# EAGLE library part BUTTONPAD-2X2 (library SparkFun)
5mm Button Pad Proven layout and schematic for 2x2 button pad. Panelize this device/fp to a 4x4 pad if needed. Spark Fun Electronics SKU : COM-07835. Compatible common cathode tri-color LED SKU : COM-00105

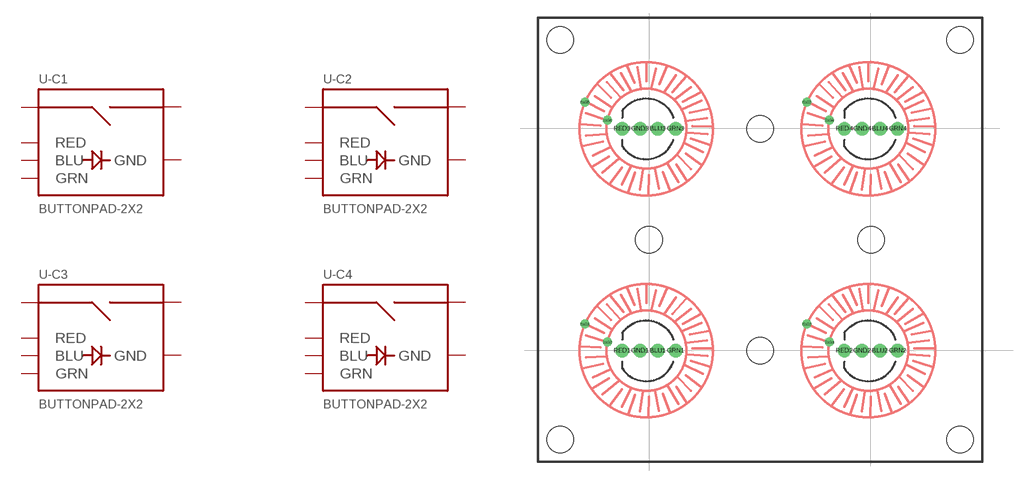
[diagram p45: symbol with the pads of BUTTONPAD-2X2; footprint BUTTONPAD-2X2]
Designator prefix -; gates -C1=BUTTONPAD_SINGLE -C2=BUTTONPAD_SINGLE -C3=BUTTONPAD_SINGLE -C4=BUTTONPAD_SINGLE

## BUTTONPAD-2X2  [BUTTONPAD-2X2]
BLU1  -C1:BLU
BLU2  -C2:BLU
BLU3  -C3:BLU
BLU4  -C4:BLU
GND1  -C1:GND
GND2  -C2:GND
GND3  -C3:GND
GND4  -C4:GND
GRN1  -C1:GRN
GRN2  -C2:GRN
GRN3  -C3:GRN
GRN4  -C4:GRN
RED1  -C1:RED
RED2  -C2:RED
RED3  -C3:RED
RED4  -C4:RED
SIG1  -C1:SIG1
SIG2  -C1:SIG2
SIG3  -C2:SIG1
SIG4  -C2:SIG2
SIG5  -C3:SIG1
SIG6  -C3:SIG2
SIG7  -C4:SIG1
SIG8  -C4:SIG2

## Footprint BUTTONPAD-2X2 (pad centres in mm)
drill 1 round: BLU1 13.5,12.5; BLU2 38.5,12.5; BLU3 13.5,37.5; BLU4 38.5,37.5; GND1 11.5,12.5; GND2 36.5,12.5; GND3 11.5,37.5; GND4 36.5,37.5; GRN1 15.5,12.5; GRN2 40.5,12.5; GRN3 15.5,37.5; GRN4 40.5,37.5; RED1 9.5,12.5; RED2 34.5,12.5; RED3 9.5,37.5; RED4 34.5,37.5
drill 0.508 round: SIG1 5.288,15.513; SIG2 7.828,13.481; SIG3 30.288,15.513; SIG4 32.828,13.481; SIG5 5.288,40.513; SIG6 7.828,38.481; SIG7 30.288,40.513; SIG8 32.828,38.481
hole 3 at 12.5,25
hole 3 at 25,37.5
hole 3 at 37.5,25
hole 3 at 25,12.5
hole 3 at 2.5,2.5
hole 3 at 2.5,47.5
hole 3 at 47.5,47.5
hole 3 at 47.5,2.5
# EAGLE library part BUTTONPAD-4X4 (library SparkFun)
5mm Button Pad Proto layout and schematic for 4x4 button pad. Spark Fun Electronics SKU : COM-07835. Compatible common cathode tri-color LED SKU : COM-00105

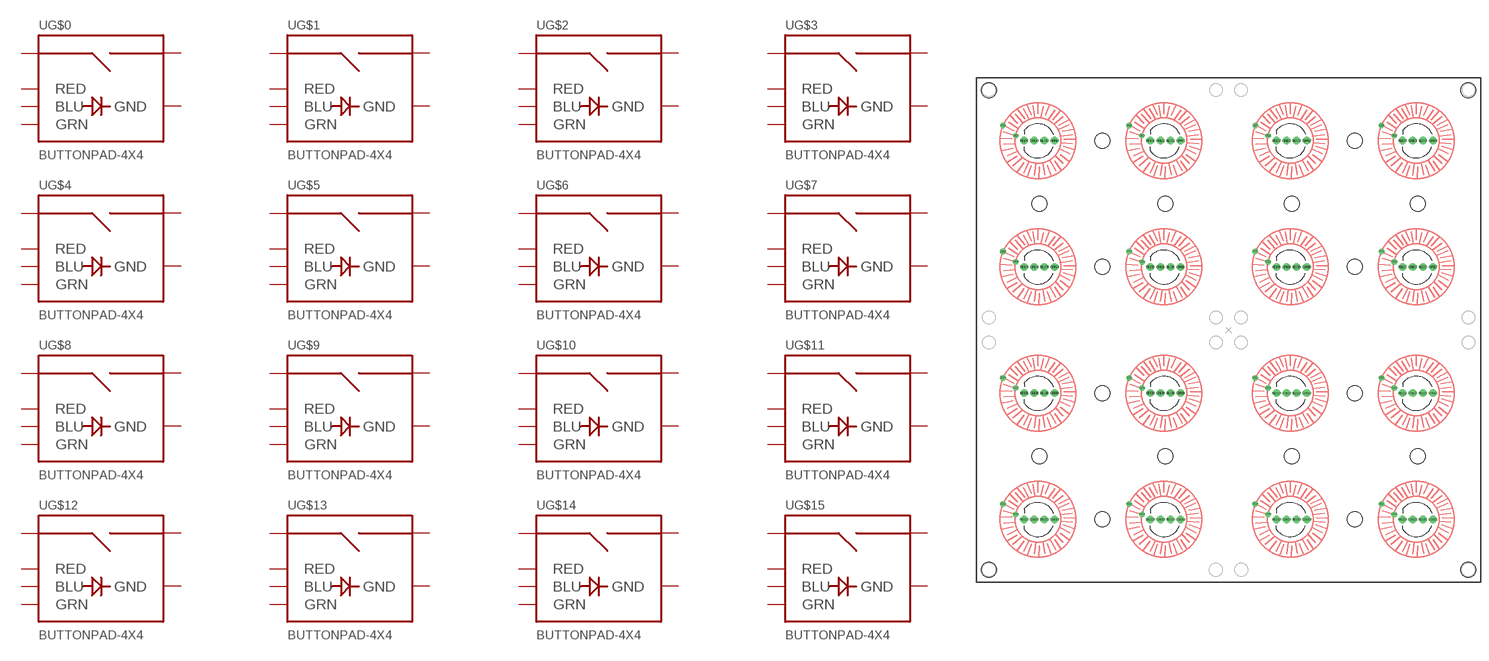
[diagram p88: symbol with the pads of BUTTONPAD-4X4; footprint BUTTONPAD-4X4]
Designator prefix -; gates G$0=BUTTONPAD_SINGLE G$1=BUTTONPAD_SINGLE G$2=BUTTONPAD_SINGLE G$3=BUTTONPAD_SINGLE G$4=BUTTONPAD_SINGLE G$5=BUTTONPAD_SINGLE G$6=BUTTONPAD_SINGLE G$7=BUTTONPAD_SINGLE G$8=BUTTONPAD_SINGLE G$9=BUTTONPAD_SINGLE G$10=BUTTONPAD_SINGLE G$11=BUTTONPAD_SINGLE G$12=BUTTONPAD_SINGLE G$13=BUTTONPAD_SINGLE G$14=BUTTONPAD_SINGLE G$15=BUTTONPAD_SINGLE

## BUTTONPAD-4X4  [BUTTONPAD-4X4]
BLU0  G$0:BLU
BLU1  G$1:BLU
BLU2  G$2:BLU
BLU3  G$3:BLU
BLU4  G$4:BLU
BLU5  G$5:BLU
BLU6  G$6:BLU
BLU7  G$7:BLU
BLU8  G$8:BLU
BLU9  G$9:BLU
BLU10  G$10:BLU
BLU11  G$11:BLU
BLU12  G$12:BLU
BLU13  G$13:BLU
BLU14  G$14:BLU
BLU15  G$15:BLU
GND0  G$0:GND
GND1  G$1:GND
GND2  G$2:GND
GND3  G$3:GND
GND4  G$4:GND
GND5  G$5:GND
GND6  G$6:GND
GND7  G$7:GND
GND8  G$8:GND
GND9  G$9:GND
GND10  G$10:GND
GND11  G$11:GND
GND12  G$12:GND
GND13  G$13:GND
GND14  G$14:GND
GND15  G$15:GND
GRN0  G$0:GRN
GRN1  G$1:GRN
GRN2  G$2:GRN
GRN3  G$3:GRN
GRN4  G$4:GRN
GRN5  G$6:GRN
GRN6  G$5:GRN
GRN7  G$7:GRN
GRN8  G$8:GRN
GRN9  G$9:GRN
GRN10  G$10:GRN
GRN11  G$11:GRN
GRN12  G$12:GRN
GRN13  G$13:GRN
GRN14  G$14:GRN
GRN15  G$15:GRN
RED0  G$0:RED
RED1  G$1:RED
RED2  G$2:RED
RED3  G$3:RED
RED4  G$4:RED
RED5  G$5:RED
RED6  G$6:RED
RED7  G$7:RED
RED8  G$8:RED
RED9  G$9:RED
RED10  G$10:RED
RED11  G$11:RED
RED12  G$12:RED
RED13  G$13:RED
RED14  G$14:RED
RED15  G$15:RED
SIG0  G$0:SIG1
SIG1  G$0:SIG2
SIG2  G$1:SIG1
SIG3  G$1:SIG2
SIG4  G$2:SIG1
SIG5  G$2:SIG2
SIG6  G$3:SIG1
SIG7  G$3:SIG2
SIG8  G$4:SIG1
SIG9  G$4:SIG2
SIG10  G$5:SIG1
SIG11  G$5:SIG2
SIG12  G$6:SIG1
SIG13  G$6:SIG2
SIG14  G$7:SIG1
SIG15  G$7:SIG2
SIG16  G$8:SIG1
SIG17  G$8:SIG2
SIG18  G$9:SIG1
SIG19  G$9:SIG2
SIG20  G$10:SIG1
SIG21  G$10:SIG2
SIG22  G$11:SIG1
SIG23  G$11:SIG2
SIG24  G$12:SIG1
SIG25  G$12:SIG2
SIG26  G$13:SIG1
SIG27  G$13:SIG2
SIG28  G$14:SIG1
SIG29  G$14:SIG2
SIG30  G$15:SIG1
SIG31  G$15:SIG2

## Footprint BUTTONPAD-4X4 (pad centres in mm)
drill 1 round: BLU0 13.5,87.5; BLU1 38.5,87.5; BLU2 63.5,87.5; BLU3 88.5,87.5; BLU4 13.5,62.5; BLU5 38.5,62.5; BLU6 63.5,62.5; BLU7 88.5,62.5; BLU8 13.5,37.5; BLU9 38.5,37.5; BLU10 63.5,37.5; BLU11 88.5,37.5; BLU12 13.5,12.5; BLU13 38.5,12.5; BLU14 63.5,12.5; BLU15 88.5,12.5; GND0 11.5,87.5; GND1 36.5,87.5; GND2 61.5,87.5; GND3 86.5,87.5; GND4 11.5,62.5; GND5 36.5,62.5; GND6 61.5,62.5; GND7 86.5,62.5; GND8 11.5,37.5; GND9 36.5,37.5; GND10 61.5,37.5; GND11 86.5,37.5; GND12 11.5,12.5; GND13 36.5,12.5; GND14 61.5,12.5; GND15 86.5,12.5; GRN0 15.5,87.5; GRN1 40.5,87.5; GRN2 65.5,87.5; GRN3 90.5,87.5; GRN4 15.5,62.5; GRN5 40.5,62.5; GRN6 65.5,62.5; GRN7 90.5,62.5; GRN8 15.5,37.5; GRN9 40.5,37.5; GRN10 65.5,37.5; GRN11 90.5,37.5; GRN12 15.5,12.5; GRN13 40.5,12.5; GRN14 65.5,12.5; GRN15 90.5,12.5; RED0 9.5,87.5; RED1 34.5,87.5; RED2 59.5,87.5; RED3 84.5,87.5; RED4 9.5,62.5; RED5 34.5,62.5; RED6 59.5,62.5; RED7 84.5,62.5; RED8 9.5,37.5; RED9 34.5,37.5; RED10 59.5,37.5; RED11 84.5,37.5; RED12 9.5,12.5; RED13 34.5,12.5; RED14 59.5,12.5; RED15 84.5,12.5
drill 0.508 round: SIG0 5.288,90.513; SIG1 7.828,88.481; SIG2 30.288,90.513; SIG3 32.828,88.481; SIG4 55.288,90.513; SIG5 57.828,88.481; SIG6 80.288,90.513; SIG7 82.828,88.481
drill 0.6 round: SIG8 5.288,65.513; SIG9 7.828,63.481; SIG10 30.288,65.513; SIG11 32.828,63.481; SIG12 55.288,65.513; SIG13 57.828,63.481; SIG14 80.288,65.513; SIG15 82.828,63.481; SIG16 5.288,40.513; SIG17 7.828,38.481; SIG18 30.288,40.513; SIG19 32.828,38.481; SIG20 55.288,40.513; SIG21 57.828,38.481; SIG22 80.288,40.513; SIG23 82.828,38.481; SIG24 5.288,15.513; SIG25 7.828,13.481; SIG26 30.288,15.513; SIG27 32.828,13.481; SIG28 55.288,15.513; SIG29 57.828,13.481; SIG30 80.288,15.513; SIG31 82.828,13.481
hole 3 at 12.5,25
hole 3 at 25,37.5
hole 3 at 37.5,25
hole 3 at 25,12.5
hole 3 at 62.5,25
hole 3 at 75,37.5
hole 3 at 87.5,25
hole 3 at 75,12.5
hole 3 at 12.5,75
hole 3 at 25,87.5
hole 3 at 37.5,75
hole 3 at 25,62.5
hole 3 at 62.5,75
hole 3 at 75,87.5
hole 3 at 87.5,75
hole 3 at 75,62.5
hole 3 at 2.484,97.516
hole 3 at 97.516,97.516
hole 3 at 97.516,2.484
hole 3 at 2.484,2.484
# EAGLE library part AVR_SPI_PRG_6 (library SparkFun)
AVR ISP 6 Pin This is the reduced ISP connector for AVR programming. Common on Arduino. This footprint will take up less PCB space and can be used with a 10-pin to 6-pin adapter such as SKU: BOB-08508

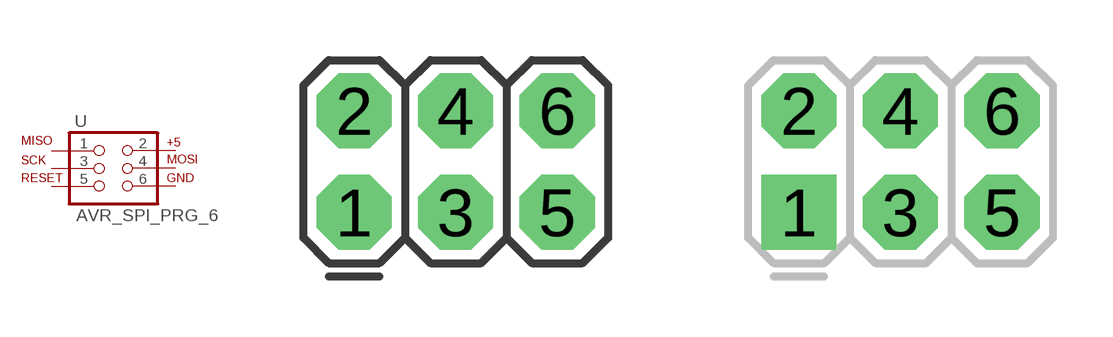
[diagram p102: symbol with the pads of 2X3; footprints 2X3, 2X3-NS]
Designator prefix -

## AVR_SPI_PRG_6PTH  [2X3]
1  1  pas
2  2  pas
3  3  pas
4  4  pas
5  5  pas
6  6  pas

## AVR_SPI_PRG_6NS  [2X3-NS]
Pads as for 2X3

## Footprint 2X3 (pad centres in mm)
drill 1.016 pad 1.88 octagon: 1 0,0; 2 0,2.54; 3 2.54,0; 4 2.54,2.54; 5 5.08,0; 6 5.08,2.54

## Footprint 2X3-NS (pad centres in mm)
drill 1.016 pad 1.88 square: 1 -2.54,-1.27
drill 1.016 pad 1.88 octagon: 2 -2.54,1.27; 3 0,-1.27; 4 0,1.27; 5 2.54,-1.27; 6 2.54,1.27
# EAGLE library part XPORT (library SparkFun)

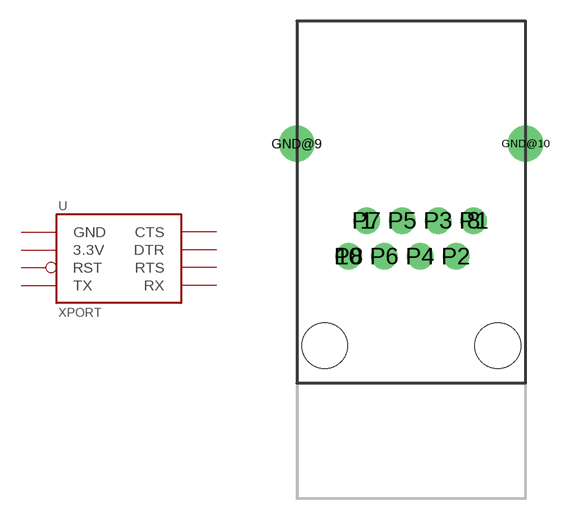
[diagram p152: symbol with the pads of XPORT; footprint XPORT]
Designator prefix -

## XPORT  [XPORT]
P1  GND
P2  3.3V
P3  RST
P4  TX
P5  RX
P6  RTS
P7  DTR
P8  CTS

## Footprint XPORT (pad centres in mm)
drill 0.889 pad 1.88 round: 1 -3.175,7.62; 8 4.445,7.62; 10 -4.445,5.08; P1 4.445,7.62; P2 3.175,5.08; P3 1.905,7.62; P4 0.635,5.08; P5 -0.635,7.62; P6 -1.905,5.08; P7 -3.175,7.62; P8 -4.445,5.08
drill 1.6 pad 2.54 round: GND@9 -8.128,13.081; GND@10 8.128,13.081
hole 3.251 at -6.147,-1.27
hole 3.251 at 6.147,-1.27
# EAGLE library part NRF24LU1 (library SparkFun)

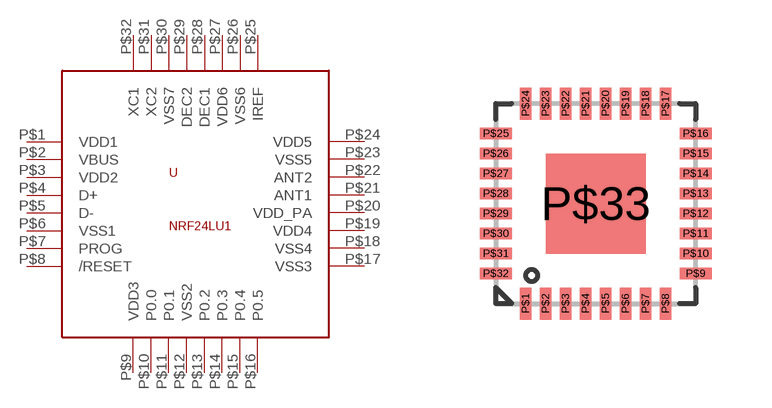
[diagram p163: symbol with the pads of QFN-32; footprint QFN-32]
Designator prefix -

## NRF24LU1  [QFN-32]
P$1  VDD1
P$2  VBUS
P$3  VDD2
P$4  D+
P$5  D-
P$6  VSS1
P$7  PROG
P$8  /RESET
P$9  VDD3
P$10  P0.0
P$11  P0.1
P$12  VSS2
P$13  P0.2
P$14  P0.3
P$15  P0.4
P$16  P0.5
P$17  VSS3
P$18  VSS4
P$19  VDD4
P$20  VDD_PA
P$21  ANT1
P$22  ANT2
P$23  VSS5
P$24  VDD5
P$25  IREF
P$26  VSS6
P$27  VDD6
P$28  DEC1
P$29  DEC2
P$30  VSS7
P$31  XC2
P$32  XC1

## Footprint QFN-32 (pad centres in mm)
smd 0.285 x 0.8: P$1 -1.75,-2.5; P$2 -1.25,-2.5; P$3 -0.75,-2.5; P$4 -0.25,-2.5; P$5 0.25,-2.5; P$6 0.75,-2.5; P$7 1.25,-2.5; P$8 1.75,-2.5; P$17 1.75,2.5; P$18 1.25,2.5; P$19 0.75,2.5; P$20 0.25,2.5; P$21 -0.25,2.5; P$22 -0.75,2.5; P$23 -1.25,2.5; P$24 -1.75,2.5
smd 0.8 x 0.285: P$9 2.5,-1.75; P$10 2.5,-1.25; P$11 2.5,-0.75; P$12 2.5,-0.25; P$13 2.5,0.25; P$14 2.5,0.75; P$15 2.5,1.25; P$16 2.5,1.75; P$25 -2.5,1.75; P$26 -2.5,1.25; P$27 -2.5,0.75; P$28 -2.5,0.25; P$29 -2.5,-0.25; P$30 -2.5,-0.75; P$31 -2.5,-1.25; P$32 -2.5,-1.75
smd 2.5 x 2.5: P$33 0,0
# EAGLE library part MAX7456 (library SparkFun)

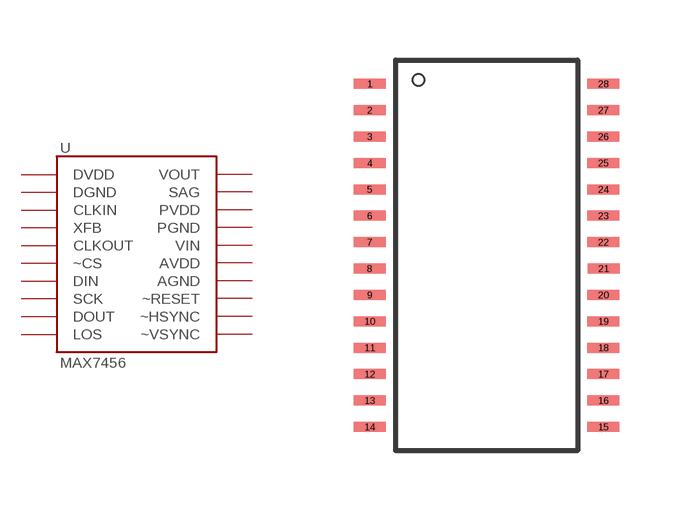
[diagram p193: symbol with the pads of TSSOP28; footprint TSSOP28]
Designator prefix -

## MAX7456  [TSSOP28]
3  DVDD
4  DGND
5  CLKIN
6  XFB
7  CLKOUT
8  ~CS
9  DIN
10  SCK
11  DOUT
12  LOS
17  ~VSYNC
18  ~HSYNC
19  ~RESET
20  AGND
21  AVDD
22  VIN
23  PGND
24  PVDD
25  SAG
26  VOUT

## Footprint TSSOP28 (pad centres in mm)
smd 0.8 x 0.25: 1 -2.921,4.623; 2 -2.921,3.962; 3 -2.921,3.302; 4 -2.921,2.642; 5 -2.921,1.981; 6 -2.921,1.321; 7 -2.921,0.66; 8 -2.927,0; 9 -2.921,-0.66; 10 -2.921,-1.321; 11 -2.921,-1.981; 12 -2.921,-2.642; 13 -2.921,-3.302; 14 -2.921,-3.962; 15 2.921,-3.962; 16 2.921,-3.302; 17 2.921,-2.642; 18 2.921,-1.981; 19 2.921,-1.321; 20 2.921,-0.66; 21 2.927,0; 22 2.921,0.66; 23 2.921,1.321; 24 2.921,1.981; 25 2.921,2.642; 26 2.921,3.302; 27 2.921,3.962; 28 2.921,4.623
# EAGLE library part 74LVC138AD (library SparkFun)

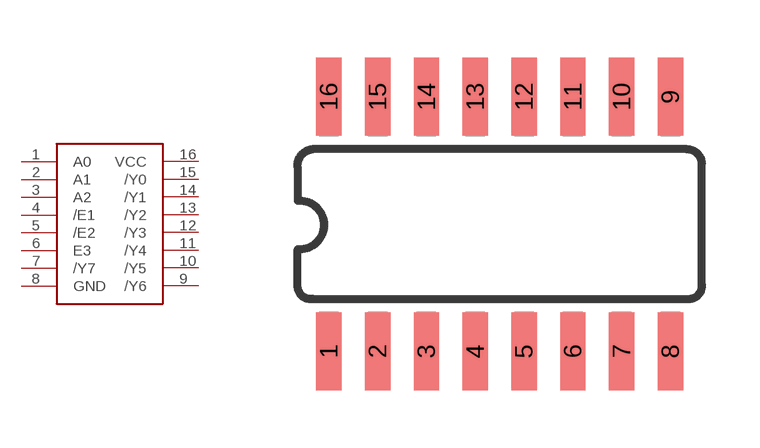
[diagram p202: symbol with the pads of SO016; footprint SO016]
Designator prefix -

## 74LVC138AD  [SO016]
1  A0
2  A1
3  A2
4  /E1
5  /E2
6  E3
7  /Y7
8  GND
9  /Y6
10  /Y5
11  /Y4
12  /Y3
13  /Y2
14  /Y1
15  /Y0
16  VCC

## Footprint SO016 (pad centres in mm)
smd 0.66 x 2.032: 1 -4.445,-3.315; 2 -3.175,-3.315; 3 -1.905,-3.315; 4 -0.635,-3.315; 5 0.635,-3.315; 6 1.905,-3.315; 7 3.175,-3.315; 8 4.445,-3.315; 9 4.445,3.315; 10 3.175,3.315; 11 1.905,3.315; 12 0.635,3.315; 13 -0.635,3.315; 14 -1.905,3.315; 15 -3.175,3.315; 16 -4.445,3.315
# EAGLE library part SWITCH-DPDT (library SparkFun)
DPDT Version of the COM-00597, MSS22 is a 125VAC @ 300mA rated switch

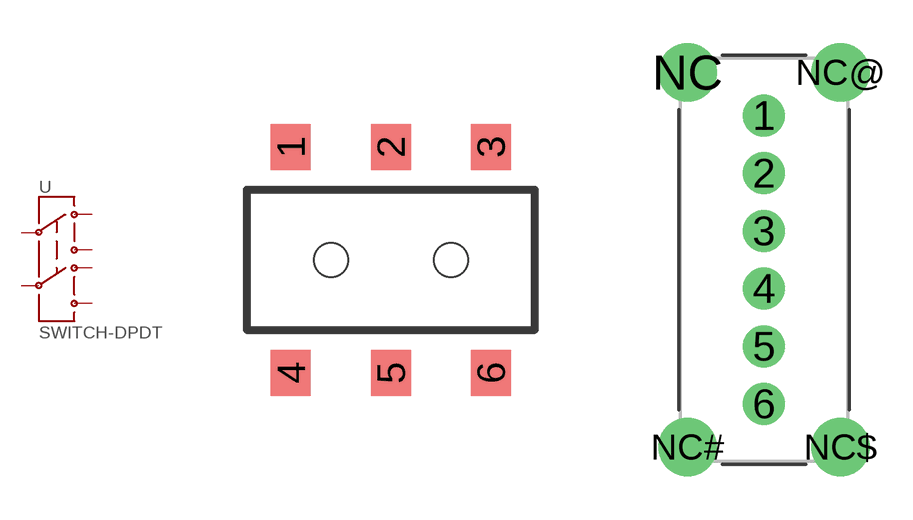
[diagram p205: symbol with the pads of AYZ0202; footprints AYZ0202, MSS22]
Designator prefix -

## SWITCH-DPDTSMD  [AYZ0202]
1  1
2  2
3  3
4  4
5  5
6  6

## SWITCH-DPDTPTH  [MSS22]
Pads as for AYZ0202

## Footprint AYZ0202 (pad centres in mm)
DPDT Slide Switch SMD www.SparkFun.com SKU : Comp-SMDS
smd 1 x 1.15: 1 -2.5,2.825; 2 0,2.825; 3 2.5,2.825; 4 -2.5,-2.825; 5 0,-2.825; 6 2.5,-2.825
hole 0.85 at 1.5,0
hole 0.85 at -1.5,0

## Footprint MSS22 (pad centres in mm)
MSS22 DPDT Switch
drill 0.95 round: 1 2.65,11.5; 2 2.65,9.5; 3 2.65,7.5; 4 2.65,5.5; 5 2.65,3.5; 6 2.65,1.5
drill 1.35 round: NC 0,13; NC# 0,0; NC$ 5.3,0; NC@ 5.3,13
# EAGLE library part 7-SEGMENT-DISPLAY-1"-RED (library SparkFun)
7-Segment Display 1" Red (COM-08546)

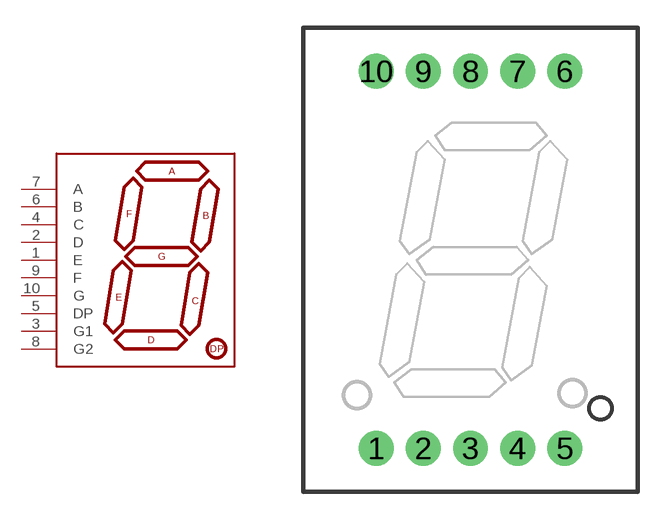
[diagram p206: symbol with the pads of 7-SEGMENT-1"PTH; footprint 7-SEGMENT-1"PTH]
Designator prefix -

## 7-SEGMENT-DISPLAY-1"-RED  [7-SEGMENT-1"PTH]
1  E
2  D
3  G1
4  C
5  DP
6  B
7  A
8  G2
9  F
10  G

## Footprint 7-SEGMENT-1"PTH (pad centres in mm)
7 Segment display Storefront SKU#: COM-08546
drill 0.8 pad 1.88 round: 1 -5.08,-10.16; 2 -2.54,-10.16; 3 0,-10.16; 4 2.54,-10.16; 5 5.08,-10.16; 6 5.08,10.16; 7 2.54,10.16; 8 0,10.16; 9 -2.54,10.16; 10 -5.08,10.16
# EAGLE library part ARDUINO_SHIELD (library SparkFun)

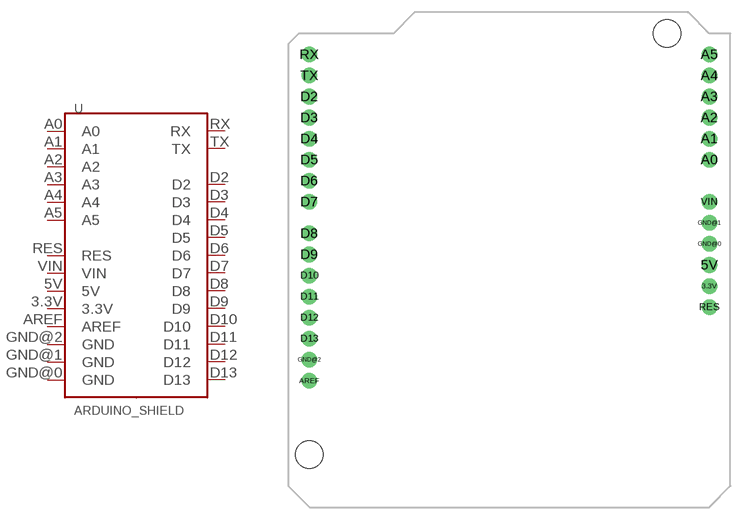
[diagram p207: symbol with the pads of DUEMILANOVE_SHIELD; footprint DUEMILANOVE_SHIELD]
Designator prefix -

## ARDUINO_SHIELD  [DUEMILANOVE_SHIELD]
3.3V  3.3V
5V  5V
A0  A0
A1  A1
A2  A2
A3  A3
A4  A4
A5  A5
AREF  AREF
D2  D2
D3  D3
D4  D4
D5  D5
D6  D6
D7  D7
D8  D8
D9  D9
D10  D10
D11  D11
D12  D12
D13  D13
GND@0  GND
GND@1  GND
GND@2  GND
RES  RES
RX  RX
TX  TX
VIN  VIN

## Footprint DUEMILANOVE_SHIELD (pad centres in mm)
drill 1.016 pad 1.88 round: 3.3V 50.8,26.67; 5V 50.8,29.21; A0 50.8,41.91; A1 50.8,44.45; A2 50.8,46.99; A3 50.8,49.53; A4 50.8,52.07; A5 50.8,54.61; AREF 2.54,15.24; D2 2.54,49.53; D3 2.54,46.99; D4 2.54,44.45; D5 2.54,41.91; D6 2.54,39.37; D7 2.54,36.83; D8 2.54,33.02; D9 2.54,30.48; D10 2.54,27.94; D11 2.54,25.4; D12 2.54,22.86; D13 2.54,20.32; GND@0 50.8,31.75; GND@1 50.8,34.29; GND@2 2.54,17.78; RES 50.8,24.13; RX 2.54,54.61; TX 2.54,52.07; VIN 50.8,36.83
hole 3.302 at 45.72,57.15
hole 3.302 at 2.54,6.35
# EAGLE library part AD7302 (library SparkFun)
AD7302

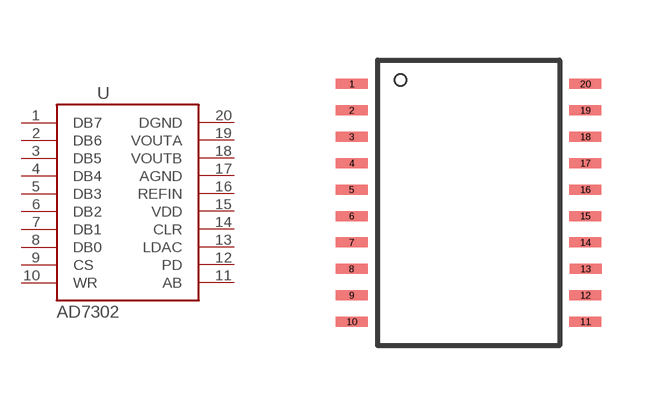
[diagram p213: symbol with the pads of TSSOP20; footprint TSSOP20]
Designator prefix -

## AD7302SMD  [TSSOP20]
1  DB7
2  DB6
3  DB5
4  DB4
5  DB3
6  DB2
7  DB1
8  DB0
9  CS
10  WR
11  AB
12  PD
13  LDAC
14  CLR
15  VDD
16  REFIN
17  AGND
18  VOUTB
19  VOUTA
20  DGND

## Footprint TSSOP20 (pad centres in mm)
smd 0.8 x 0.25: 1 -2.921,2.623; 2 -2.921,1.962; 3 -2.921,1.302; 4 -2.921,0.642; 5 -2.921,-0.019; 6 -2.921,-0.679; 7 -2.921,-1.34; 8 -2.927,-2; 9 -2.921,-2.66; 10 -2.921,-3.321; 11 2.921,-3.321; 12 2.921,-2.66; 13 2.927,-2; 14 2.921,-1.34; 15 2.921,-0.679; 16 2.921,-0.019; 17 2.921,0.642; 18 2.921,1.302; 19 2.921,1.962; 20 2.921,2.623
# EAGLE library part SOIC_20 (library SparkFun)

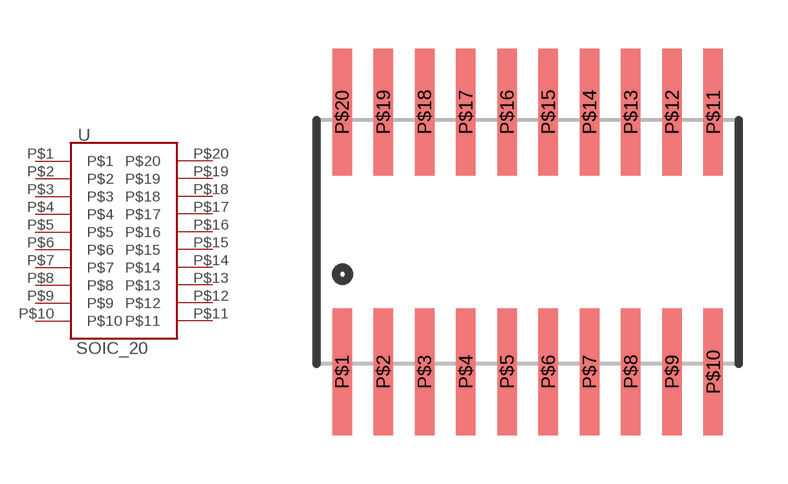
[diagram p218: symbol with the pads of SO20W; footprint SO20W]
Designator prefix -

## SOIC_20  [SO20W]
P$1  P$1
P$2  P$2
P$3  P$3
P$4  P$4
P$5  P$5
P$6  P$6
P$7  P$7
P$8  P$8
P$9  P$9
P$10  P$10
P$11  P$11
P$12  P$12
P$13  P$13
P$14  P$14
P$15  P$15
P$16  P$16
P$17  P$17
P$18  P$18
P$19  P$19
P$20  P$20

## Footprint SO20W (pad centres in mm)
20 pin soic package that should fit both wide and narrow, UNPROOVEN
smd 0.6 x 3.9: P$1 -5.715,-4; P$2 -4.445,-4; P$3 -3.175,-4; P$4 -1.905,-4; P$5 -0.635,-4; P$6 0.635,-4; P$7 1.905,-4; P$8 3.175,-4; P$9 4.445,-4; P$10 5.715,-4; P$11 5.715,4; P$12 4.445,4; P$13 3.175,4; P$14 1.905,4; P$15 0.635,4; P$16 -0.635,4; P$17 -1.905,4; P$18 -3.175,4; P$19 -4.445,4; P$20 -5.715,4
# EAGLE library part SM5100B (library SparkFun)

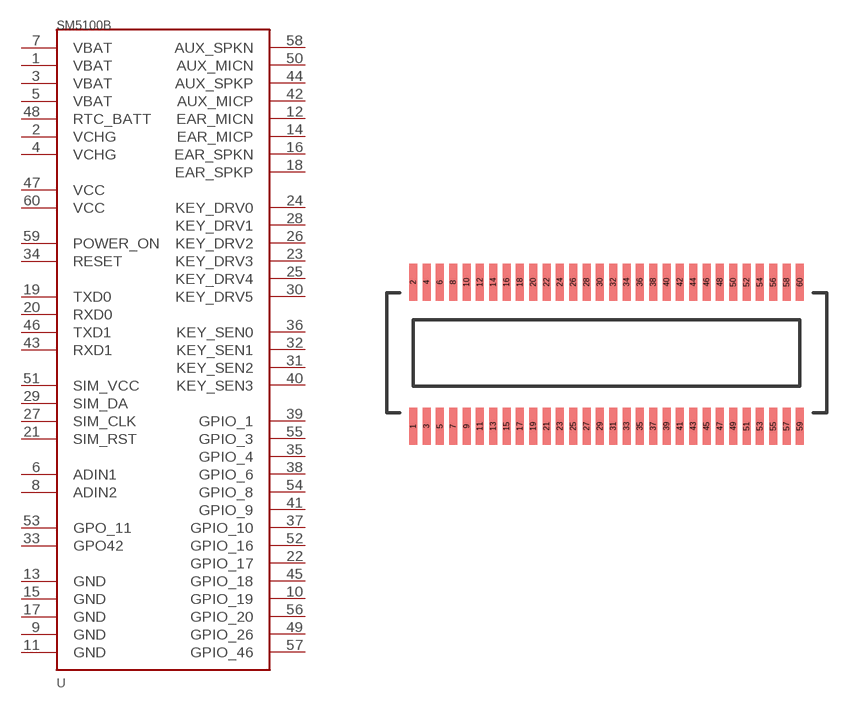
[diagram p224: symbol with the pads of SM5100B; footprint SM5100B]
Designator prefix -

## SM5100B  [SM5100B]
1  VBAT
2  VCHG
3  VBAT
4  VCHG
5  VBAT
6  ADIN1
7  VBAT
8  ADIN2
9  GND
10  GPIO_19
11  GND
12  EAR_MICN
13  GND
14  EAR_MICP
15  GND
16  EAR_SPKN
17  GND
18  EAR_SPKP
19  TXD0
20  RXD0
21  SIM_RST
22  GPIO_17
23  KEY_DRV3
24  KEY_DRV0
25  KEY_DRV4
26  KEY_DRV2
27  SIM_CLK
28  KEY_DRV1
29  SIM_DA
30  KEY_DRV5
31  KEY_SEN2
32  KEY_SEN1
33  GPO42
34  RESET
35  GPIO_4
36  KEY_SEN0
37  GPIO_10
38  GPIO_6
39  GPIO_1
40  KEY_SEN3
41  GPIO_9
42  AUX_MICP
43  RXD1
44  AUX_SPKP
45  GPIO_18
46  TXD1
47  VCC
48  RTC_BATT
49  GPIO_26
50  AUX_MICN
51  SIM_VCC
52  GPIO_16
53  GPO_11
54  GPIO_8
55  GPIO_3
56  GPIO_20
57  GPIO_46
58  AUX_SPKN
59  POWER_ON
60  VCC

## Footprint SM5100B (pad centres in mm)
smd 0.3 x 1.4: 1 -7.25,-2.7; 2 -7.25,2.7; 3 -6.75,-2.7; 4 -6.75,2.7; 5 -6.25,-2.7; 6 -6.25,2.7; 7 -5.75,-2.7; 8 -5.75,2.7; 9 -5.25,-2.7; 10 -5.25,2.7; 11 -4.75,-2.7; 12 -4.75,2.7; 13 -4.25,-2.7; 14 -4.25,2.7; 15 -3.75,-2.7; 16 -3.75,2.7; 17 -3.25,-2.7; 18 -3.25,2.7; 19 -2.75,-2.7; 20 -2.75,2.7; 21 -2.25,-2.7; 22 -2.25,2.7; 23 -1.75,-2.7; 24 -1.75,2.7; 25 -1.25,-2.7; 26 -1.25,2.7; 27 -0.75,-2.7; 28 -0.75,2.7; 29 -0.25,-2.7; 30 -0.25,2.7; 31 0.25,-2.7; 32 0.25,2.7; 33 0.75,-2.7; 34 0.75,2.7; 35 1.25,-2.7; 36 1.25,2.7; 37 1.75,-2.7; 38 1.75,2.7; 39 2.25,-2.7; 40 2.25,2.7; 41 2.75,-2.7; 42 2.75,2.7; 43 3.25,-2.7; 44 3.25,2.7; 45 3.75,-2.7; 46 3.75,2.7; 47 4.25,-2.7; 48 4.25,2.7; 49 4.75,-2.7; 50 4.75,2.7; 51 5.25,-2.7; 52 5.25,2.7; 53 5.75,-2.7; 54 5.75,2.7; 55 6.25,-2.7; 56 6.25,2.7; 57 6.75,-2.7; 58 6.75,2.7; 59 7.25,-2.7; 60 7.25,2.7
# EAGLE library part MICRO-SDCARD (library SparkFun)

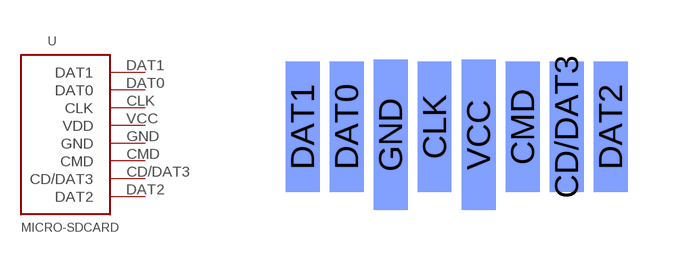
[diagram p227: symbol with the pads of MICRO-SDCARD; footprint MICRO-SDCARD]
Designator prefix -

## MICRO-SDCARD  [MICRO-SDCARD]
CD/DAT3  CD/DAT3
CLK  CLK
CMD  CMD
DAT0  DAT0
DAT1  DAT1
DAT2  DAT2
GND  GND
VCC  VDD

## Footprint MICRO-SDCARD (pad centres in mm)
smd 0.85 x 3.25 bottom: CD/DAT3 7.6,2.3; CLK 4.3,2.3; CMD 6.5,2.3; DAT0 2.1,2.3; DAT1 1,2.3; DAT2 8.7,2.3
smd 0.85 x 3.75 bottom: GND 3.2,2.1; VCC 5.4,2.1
